VERSION 5.7 ;
BUSBITCHARS "[]" ;
DIVIDERCHAR "/" ;
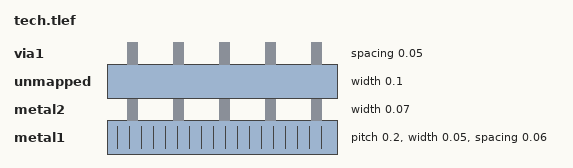
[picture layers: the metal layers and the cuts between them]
LAYER metal1
  TYPE ROUTING ;
  WIDTH 0.05 ;
  SPACING 0.06 ;
  SPACING 0.08 RANGE 0.5 10 ;
  PITCH 0.2 ;
  DIRECTION VERTICAL ;
END metal1
LAYER metal2
  TYPE CUT ;
  WIDTH 0.07 ;
END metal2
LAYER unmapped
  TYPE ROUTING ;
  WIDTH 0.1 ;
END unmapped
LAYER via1
  TYPE CUT ;
  SPACING 0.05 ;
END via1
END LIBRARY
